VERSION 5.7 ;
  NOWIREEXTENSIONATPIN ON ;
  DIVIDERCHAR "/" ;
  BUSBITCHARS "[]" ;
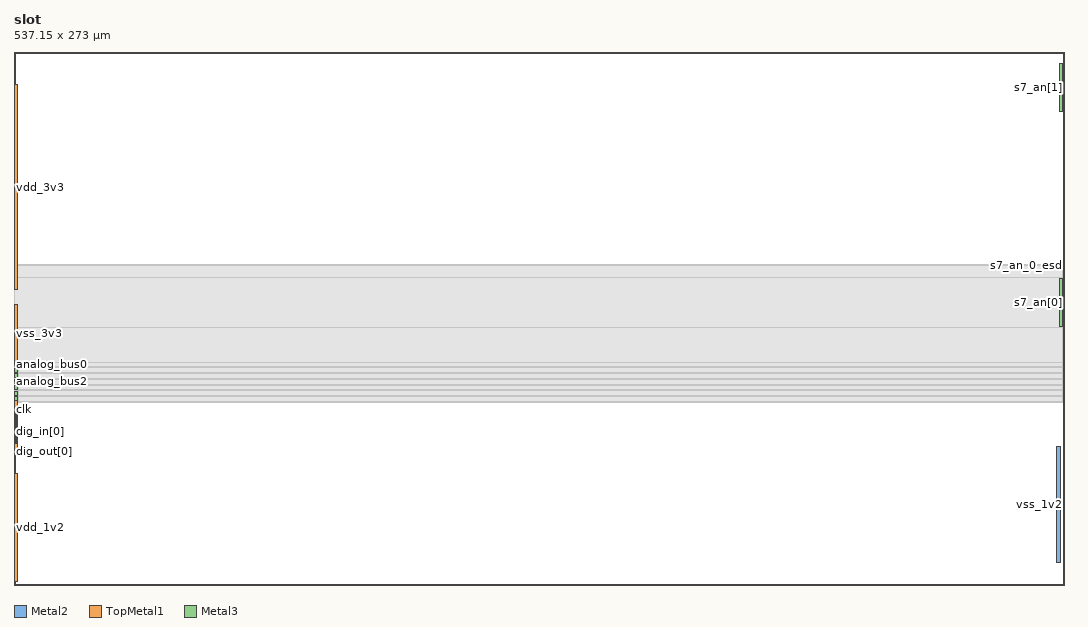
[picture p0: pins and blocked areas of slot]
MACRO slot
  CLASS BLOCK ;
  FOREIGN slot ;
  ORIGIN 0.000 0.000 ;
  SIZE 537.150 BY 273.000 ;
  PIN vss_1v2
    PORT
      LAYER Metal2 ;
        RECT 533.150 11.635 535.150 71.055 ;
    END
    PORT
      LAYER TopMetal1 ;
        RECT 0.000 66.365 2.000 96.365 ;
    END
  END vss_1v2
  PIN vdd_1v2
    PORT
      LAYER TopMetal1 ;
        RECT 0.000 2.000 2.000 56.795 ;
    END
  END vdd_1v2
  PIN vss_3v3
    PORT
      LAYER TopMetal1 ;
        RECT 0.000 113.545 2.000 143.545 ;
    END
  END vss_3v3
  PIN vdd_3v3
    PORT
      LAYER TopMetal1 ;
        RECT 0.000 151.120 2.000 256.080 ;
    END
  END vdd_3v3
  PIN s7_an[0]
    PORT
      LAYER Metal3 ;
        RECT 535.050 132.160 536.440 156.930 ;
    END
  END s7_an[0]
  PIN s7_an[1]
    PORT
      LAYER Metal3 ;
        RECT 535.050 242.160 536.440 266.930 ;
    END
  END s7_an[1]
  PIN s7_an_0_esd
    PORT
      LAYER Metal3 ;
        RECT 535.150 163.415 537.150 163.905 ;
    END
  END s7_an_0_esd
  PIN vbias
    PORT
      LAYER Metal3 ;
        RECT 0.000 94.215 2.000 96.215 ;
    END
  END vbias
  PIN dig_in[23]
    PORT
      LAYER Metal3 ;
        RECT 0.000 88.470 2.000 88.690 ;
    END
  END dig_in[23]
  PIN dig_in[22]
    PORT
      LAYER Metal3 ;
        RECT 0.000 88.030 2.000 88.250 ;
    END
  END dig_in[22]
  PIN dig_in[21]
    PORT
      LAYER Metal3 ;
        RECT 0.000 87.590 2.000 87.810 ;
    END
  END dig_in[21]
  PIN dig_in[20]
    PORT
      LAYER Metal3 ;
        RECT 0.000 87.150 2.000 87.370 ;
    END
  END dig_in[20]
  PIN dig_in[19]
    PORT
      LAYER Metal3 ;
        RECT 0.000 86.710 2.000 86.930 ;
    END
  END dig_in[19]
  PIN dig_in[18]
    PORT
      LAYER Metal3 ;
        RECT 0.000 86.270 2.000 86.490 ;
    END
  END dig_in[18]
  PIN dig_in[17]
    PORT
      LAYER Metal3 ;
        RECT 0.000 85.830 2.000 86.050 ;
    END
  END dig_in[17]
  PIN dig_in[16]
    PORT
      LAYER Metal3 ;
        RECT 0.000 85.390 2.000 85.610 ;
    END
  END dig_in[16]
  PIN dig_in[15]
    PORT
      LAYER Metal3 ;
        RECT 0.000 84.950 2.000 85.170 ;
    END
  END dig_in[15]
  PIN dig_in[14]
    PORT
      LAYER Metal3 ;
        RECT 0.000 84.510 2.000 84.730 ;
    END
  END dig_in[14]
  PIN dig_in[13]
    PORT
      LAYER Metal3 ;
        RECT 0.000 84.070 2.000 84.290 ;
    END
  END dig_in[13]
  PIN dig_in[12]
    PORT
      LAYER Metal3 ;
        RECT 0.000 83.630 2.000 83.850 ;
    END
  END dig_in[12]
  PIN dig_in[11]
    PORT
      LAYER Metal3 ;
        RECT 0.000 83.190 2.000 83.410 ;
    END
  END dig_in[11]
  PIN dig_in[10]
    PORT
      LAYER Metal3 ;
        RECT 0.000 82.750 2.000 82.970 ;
    END
  END dig_in[10]
  PIN dig_in[9]
    PORT
      LAYER Metal3 ;
        RECT 0.000 82.310 2.000 82.530 ;
    END
  END dig_in[9]
  PIN dig_in[8]
    PORT
      LAYER Metal3 ;
        RECT 0.000 81.870 2.000 82.090 ;
    END
  END dig_in[8]
  PIN dig_in[7]
    PORT
      LAYER Metal3 ;
        RECT 0.000 81.430 2.000 81.650 ;
    END
  END dig_in[7]
  PIN dig_in[6]
    PORT
      LAYER Metal3 ;
        RECT 0.000 80.990 2.000 81.210 ;
    END
  END dig_in[6]
  PIN dig_in[5]
    PORT
      LAYER Metal3 ;
        RECT 0.000 80.550 2.000 80.770 ;
    END
  END dig_in[5]
  PIN dig_in[4]
    PORT
      LAYER Metal3 ;
        RECT 0.000 80.110 2.000 80.330 ;
    END
  END dig_in[4]
  PIN dig_in[3]
    PORT
      LAYER Metal3 ;
        RECT 0.000 79.670 2.000 79.890 ;
    END
  END dig_in[3]
  PIN dig_in[2]
    PORT
      LAYER Metal3 ;
        RECT 0.000 79.230 2.000 79.450 ;
    END
  END dig_in[2]
  PIN dig_in[1]
    PORT
      LAYER Metal3 ;
        RECT 0.000 78.790 2.000 79.010 ;
    END
  END dig_in[1]
  PIN dig_in[0]
    PORT
      LAYER Metal3 ;
        RECT 0.000 78.350 2.000 78.570 ;
    END
  END dig_in[0]
  PIN dig_out[11]
    PORT
      LAYER Metal3 ;
        RECT 0.000 77.030 2.000 77.250 ;
    END
  END dig_out[11]
  PIN dig_out[10]
    PORT
      LAYER Metal3 ;
        RECT 0.000 76.590 2.000 76.810 ;
    END
  END dig_out[10]
  PIN dig_out[9]
    PORT
      LAYER Metal3 ;
        RECT 0.000 76.150 2.000 76.370 ;
    END
  END dig_out[9]
  PIN dig_out[8]
    PORT
      LAYER Metal3 ;
        RECT 0.000 75.710 2.000 75.930 ;
    END
  END dig_out[8]
  PIN dig_out[7]
    PORT
      LAYER Metal3 ;
        RECT 0.000 75.270 2.000 75.490 ;
    END
  END dig_out[7]
  PIN dig_out[6]
    PORT
      LAYER Metal3 ;
        RECT 0.000 74.830 2.000 75.050 ;
    END
  END dig_out[6]
  PIN dig_out[5]
    PORT
      LAYER Metal3 ;
        RECT 0.000 74.390 2.000 74.610 ;
    END
  END dig_out[5]
  PIN dig_out[4]
    PORT
      LAYER Metal3 ;
        RECT 0.000 73.950 2.000 74.170 ;
    END
  END dig_out[4]
  PIN dig_out[3]
    PORT
      LAYER Metal3 ;
        RECT 0.000 73.510 2.000 73.730 ;
    END
  END dig_out[3]
  PIN dig_out[2]
    PORT
      LAYER Metal3 ;
        RECT 0.000 73.070 2.000 73.290 ;
    END
  END dig_out[2]
  PIN dig_out[1]
    PORT
      LAYER Metal3 ;
        RECT 0.000 72.630 2.000 72.850 ;
    END
  END dig_out[1]
  PIN dig_out[0]
    PORT
      LAYER Metal3 ;
        RECT 0.000 72.190 2.000 72.410 ;
    END
  END dig_out[0]
  PIN ibias0
    PORT
      LAYER Metal3 ;
        RECT 0.000 97.155 2.000 99.155 ;
    END
  END ibias0
  PIN ibias1
    PORT
      LAYER Metal3 ;
        RECT 0.000 100.095 2.000 102.095 ;
    END
  END ibias1
  PIN analog_bus3
    PORT
      LAYER Metal3 ;
        RECT 0.000 103.035 2.000 105.035 ;
    END
  END analog_bus3
  PIN analog_bus2
    PORT
      LAYER Metal3 ;
        RECT 0.000 105.975 2.000 107.975 ;
    END
  END analog_bus2
  PIN analog_bus1
    PORT
      LAYER Metal3 ;
        RECT 0.000 108.915 2.000 110.915 ;
    END
  END analog_bus1
  PIN analog_bus0
    PORT
      LAYER Metal3 ;
        RECT 0.000 111.855 2.000 113.855 ;
    END
  END analog_bus0
  PIN enable
    PORT
      LAYER Metal3 ;
        RECT 0.000 89.360 2.000 89.580 ;
    END
  END enable
  PIN clk
    PORT
      LAYER Metal3 ;
        RECT 0.000 89.800 2.000 90.020 ;
    END
  END clk
  PIN reset
    PORT
      LAYER Metal3 ;
        RECT 0.000 88.910 2.000 89.130 ;
    END
  END reset
  OBS
      LAYER Metal3 ;
        RECT 0.000 163.205 534.940 163.910 ;
        RECT 0.000 157.140 536.440 163.205 ;
        RECT 0.000 131.950 534.840 157.140 ;
        RECT 0.000 114.065 536.440 131.950 ;
        RECT 2.210 111.645 536.440 114.065 ;
        RECT 0.000 111.125 536.440 111.645 ;
        RECT 2.210 108.705 536.440 111.125 ;
        RECT 0.000 108.185 536.440 108.705 ;
        RECT 2.210 105.765 536.440 108.185 ;
        RECT 0.000 105.245 536.440 105.765 ;
        RECT 2.210 102.825 536.440 105.245 ;
        RECT 0.000 102.305 536.440 102.825 ;
        RECT 2.210 99.885 536.440 102.305 ;
        RECT 0.000 99.365 536.440 99.885 ;
        RECT 2.210 96.945 536.440 99.365 ;
        RECT 0.000 96.425 536.440 96.945 ;
        RECT 2.210 94.005 536.440 96.425 ;
        RECT 0.000 93.615 536.440 94.005 ;
  END
END slot
END LIBRARY

